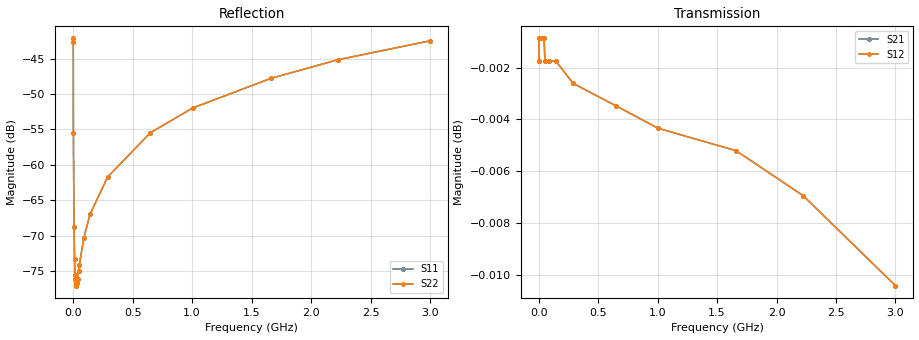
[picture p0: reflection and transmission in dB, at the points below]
! S-Parameter Data Generated by TDK Corporation
! Copyright(C) 2024 TDK Corporation.
! All Rights Reserved.
! TDK P/N: CLLC1AX7S0G684M050AC (Multilayer Ceramic Chip Capacitor)
! Property: C=680nF
! Size(LxWxT): 1.6x0.8x0.5mm
! Model Type: s2p (Touchstone File Format Version 1.0)
! Frequency: DC=Yes Start=0.3MHz Stop=3000MHz 402points Log-sweep
! Model Generated on May 28, 2024
! Terms and conditions regarding TDK Simulation Models:
! 1)This simulation model is being provided solely for informational
!  purposes. Please refer to the specifications of the products in
!  terms of detailed characteristics of such products.
! 2)In no event shall TDK Corporation of any of its subsidiaries be
!  liable for any loss or damage arising, directly or indirectly,
!  from any information contained in this simulation model, including,
!  but not limited to loss or damages arising from any inaccuracies,
!  omissions or errors in connection with such information.
! 3)Any and all copyrights on this simulation model are owned by
!  TDK Corporation.  Duplication or redistribution of this simulation
!  model without prior written permission from TDK Corporation
!  is prohibited.
! 4)This simulation model is subject to any modification or change
!  without any prior notice.
! 5)Neither TDK Corporation nor any of its subsidiaries shall make any
!  warranty, express or implied, including but not limited to the
!  correctness, implied warranties of merchantability and fitness for
!  a particular purpose with respect to this simulation models.
! 6)The use of this simulation model shall be deemed to have consented
!  to the terms and conditions hereof.
! Port Assignments:
!  1 ---| |--- 2
! Applicable Conditions:
!  Temperature = 25 degC
!  DC Bias Voltage = 0 V
!  Small Signal Operation
# Hz S MA R 50
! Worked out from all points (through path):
!   401 points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, 300 kHz to 3 GHz, reference 50 ohm
!   highest |S21| = 0.00 dB at 6.478 MHz (marker M1); lowest = 0.0 dB at 3 GHz (marker M2)
!   lowest |S11| = -77.0 dB at 25.23 MHz (marker M3), VSWR 1.00, Z = 50 - j0.000463 ohm
!   |S11| at or under -10 dB: start of sweep to end of sweep
!   |S22| runs from -77.0 to -42.2 dB; largest |S21 - S12| = 0
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300000  0.007804 -88.2  0.9998 0.4  0.9998 0.4  0.007804 -88.2
316106  0.007409 -88.2  0.9998 0.4  0.9998 0.4  0.007409 -88.2
1417447  0.001666 -85.1  0.9999 0.1  0.9999 0.1  0.001666 -85.1
6477617  0.0003666 -69.0  0.9999 0.0  0.9999 0.0  0.0003666 -69.0
1.114606e7  0.0002171 -52.1  0.9999 0.0  0.9999 0.0  0.0002171 -52.1
1.538584e7  0.0001668 -35.7  0.9999 0.0  0.9999 0.0  0.0001668 -35.7
1.70121e7  0.0001569 -29.4  0.9999 0.0  0.9999 0.0  0.0001569 -29.4
1.912524e7  0.0001484 -21.3  0.9999 0.0  0.9999 0.0  0.0001484 -21.3
2.173308e7  0.0001432 -12.2  0.9999 0.0  0.9999 0.0  0.0001432 -12.2
2.52334e7  0.0001407 -1.9  0.9999 0.0  0.9999 0.0  0.0001407 -1.9
3e7  0.0001459 9.5  0.9999 -0.0  0.9999 -0.0  0.0001459 9.5
3.652087e7  0.0001581 22.5  0.9999 -0.0  0.9999 -0.0  0.0001581 22.5
4.465116e7  0.0001781 32.7  0.9999 -0.0  0.9999 -0.0  0.0001781 32.7
5.147625e7  0.0001976 38.9  0.9998 -0.0  0.9998 -0.0  0.0001976 38.9
8.952162e7  0.0003071 55.6  0.9998 -0.0  0.9998 -0.0  0.0003071 55.6
1.416118e8  0.0004489 63.7  0.9998 -0.0  0.9998 -0.0  0.0004489 63.7
2.881901e8  0.0008189 72.0  0.9997 -0.0  0.9997 -0.0  0.0008189 72.0
6.485268e8  0.001686 77.7  0.9996 -0.1  0.9996 -0.1  0.001686 77.7
1.003707e9  0.002516 79.6  0.9995 -0.1  0.9995 -0.1  0.002516 79.6
1.659977e9  0.004068 81.0  0.9994 -0.2  0.9994 -0.2  0.004068 81.0
2.223931e9  0.005509 81.3  0.9992 -0.3  0.9992 -0.3  0.005509 81.3
3e9  0.007496 80.5  0.9988 -0.4  0.9988 -0.4  0.007496 80.5
